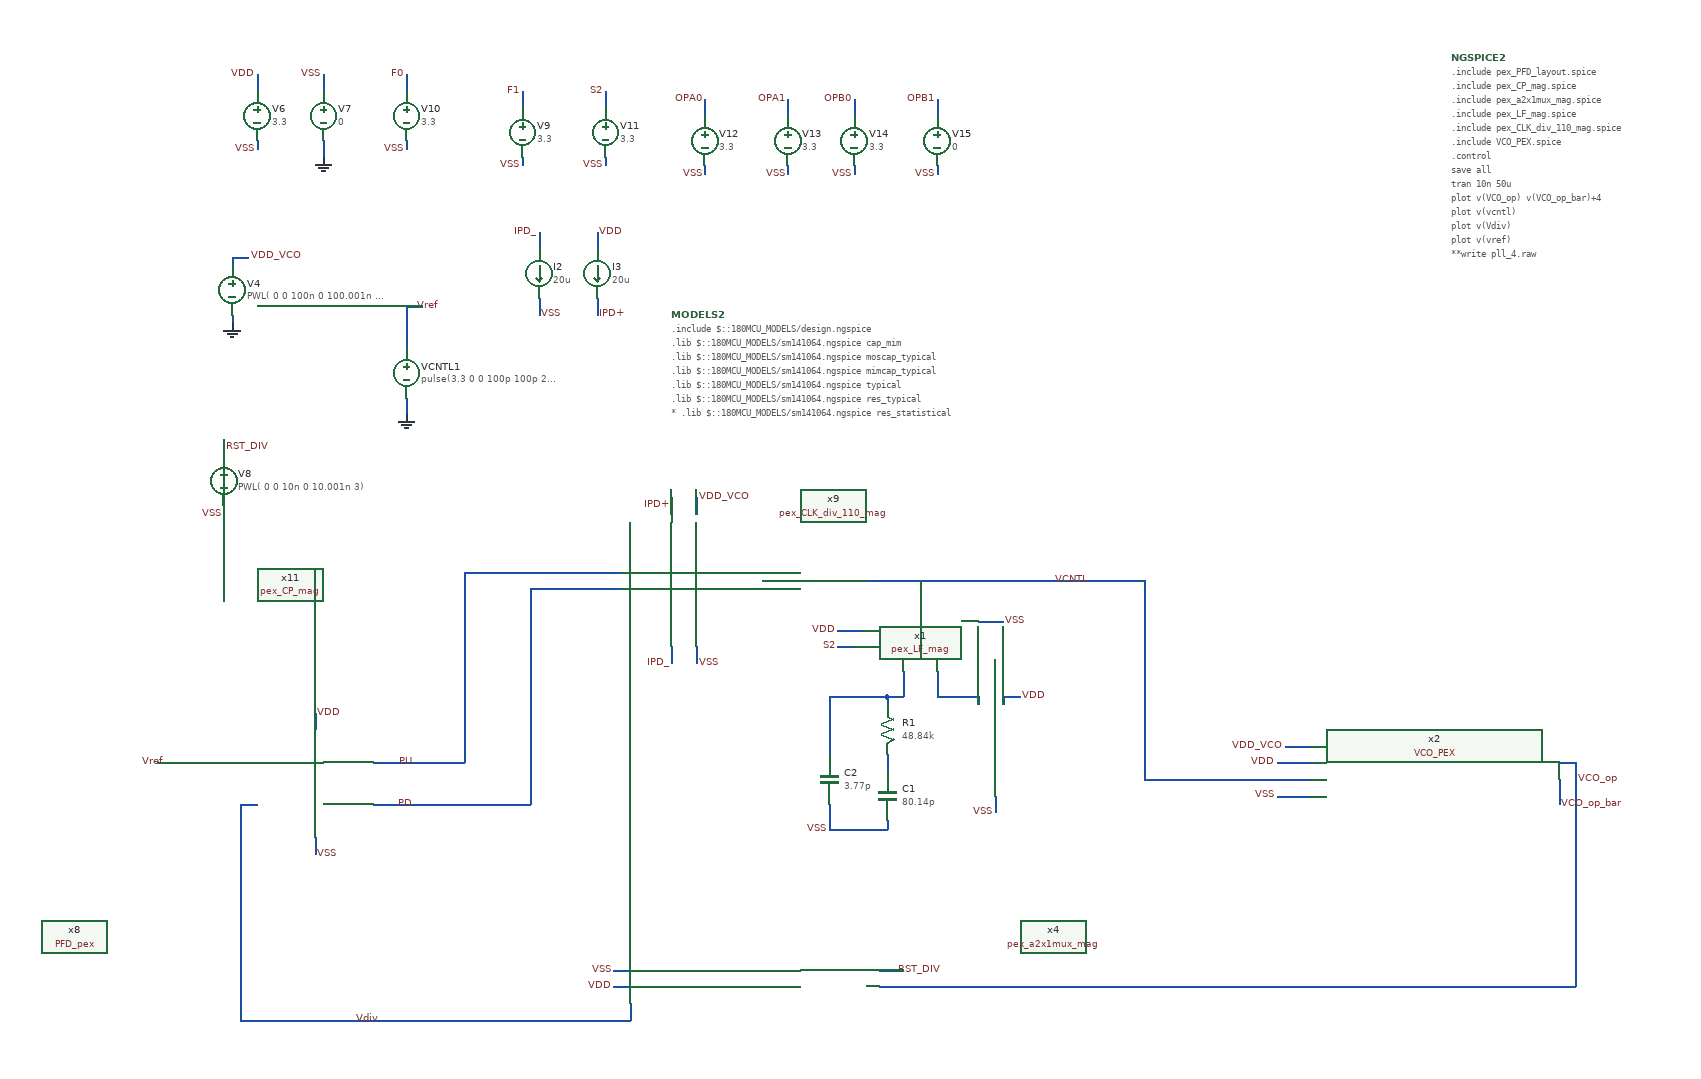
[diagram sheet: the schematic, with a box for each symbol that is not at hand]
v {xschem version=3.1.0 file_version=1.2
}
G {}
K {}
V {}
S {}
E {}
N 270 -490 270 -470 {
lab=VDD}
N 270 -340 270 -320 {
lab=VSS}
N 180 -430 200 -430 {
lab=Vref}
N 180 -380 200 -380 {
lab=Vdiv}
N 340 -380 360 -380 {
lab=PD}
N 100 -430 160 -430 {
lab=Vref}
N 160 -430 180 -430 {
lab=Vref}
N 360 -430 450 -430 {
lab=PU}
N 360 -380 450 -380 {
lab=PD}
N 180 -380 180 -250 {
lab=Vdiv}
N 180 -150 180 -120 {
lab=Vdiv}
N 190 -120 480 -120 {
lab=Vdiv}
N 180 -250 180 -150 {
lab=Vdiv}
N 180 -120 190 -120 {
lab=Vdiv}
N 340 -430 360 -430 {
lab=PU}
N 380 -870 380 -850 {
lab=GND}
N 170 -970 170 -960 {
lab=GND}
N 380 -980 400 -980 {
lab=Vref}
N 200 -1180 200 -1170 {
lab=VSS}
N 200 -1260 200 -1240 {
lab=VDD}
N 280 -1260 280 -1240 {
lab=VSS}
N 280 -1180 280 -1160 {
lab=GND}
N 480 -120 650 -120 {
lab=Vdiv}
N 980 -160 1630 -160 {
lab=VCO_op}
N 160 -740 160 -730 {
lab=VSS}
N 160 -820 160 -800 {
lab=RST_DIV}
N 1790 -410 1790 -390 {
lab=VCO_op}
N 380 -980 380 -930 {
lab=Vref}
N 950 -160 970 -160 {
lab=VCO_op}
N 970 -160 980 -160 {
lab=VCO_op}
N 170 -1040 170 -1030 {
lab=VDD_VCO}
N 170 -1040 190 -1040 {
lab=VDD_VCO}
N 520 -1160 520 -1150 {
lab=VSS}
N 520 -1240 520 -1220 {
lab=F1}
N 380 -1180 380 -1170 {
lab=VSS}
N 380 -1260 380 -1240 {
lab=F0}
N 620 -1160 620 -1150 {
lab=VSS}
N 620 -1240 620 -1220 {
lab=S2}
N 740 -1150 740 -1140 {
lab=VSS}
N 740 -1230 740 -1210 {
lab=OPA0}
N 840 -1150 840 -1140 {
lab=VSS}
N 840 -1230 840 -1210 {
lab=OPA1}
N 920 -1150 920 -1140 {
lab=VSS}
N 920 -1230 920 -1210 {
lab=OPB0}
N 1020 -1150 1020 -1140 {
lab=VSS}
N 1020 -1230 1020 -1210 {
lab=OPB1}
N 730 -750 730 -730 {
lab=VDD_VCO}
N 730 -570 730 -550 {
lab=VSS}
N 620 -660 640 -660 {
lab=PU}
N 620 -640 640 -640 {
lab=PD}
N 700 -750 700 -730 {
lab=IPD+}
N 700 -570 700 -550 {
lab=IPD_}
N 540 -990 540 -970 {
lab=VSS}
N 610 -990 610 -970 {
lab=IPD+}
N 540 -1070 540 -1050 {
lab=IPD_}
N 610 -1070 610 -1050 {
lab=VDD}
N 80 -430 110 -430 {
lab=Vref}
N 1270 -410 1310 -410 {
lab=VCNTL}
N 1790 -430 1790 -410 {
lab=VCO_op}
N 1770 -430 1790 -430 {
lab=VCO_op}
N 1770 -410 1770 -380 {
lab=VCO_op_bar}
N 650 -140 650 -120 {
lab=Vdiv}
N 640 -160 650 -160 {
lab=VDD}
N 630 -160 640 -160 {
lab=VDD}
N 630 -180 650 -180 {
lab=VSS}
N 950 -180 980 -180 {
lab=RST_DIV}
N 1440 -450 1470 -450 {
lab=VDD_VCO}
N 1310 -410 1470 -410 {
lab=VCNTL}
N 1090 -390 1090 -370 {
lab=VSS}
N 1100 -510 1100 -500 {
lab=VDD}
N 1100 -510 1120 -510 {
lab=VDD}
N 900 -570 920 -570 {
lab=S2}
N 900 -590 920 -590 {
lab=VDD}
N 1070 -600 1100 -600 {
lab=VSS}
N 890 -380 890 -350 {
lab=VSS}
N 890 -350 960 -350 {
lab=VSS}
N 890 -510 890 -440 {
lab=#net1}
N 890 -510 960 -510 {
lab=#net1}
N 960 -510 960 -500 {
lab=#net1}
N 920 -590 930 -590 {
lab=VDD}
N 880 -650 1060 -650 {
lab=VCNTL}
N 960 -440 960 -420 {
lab=#net2}
N 960 -360 960 -350 {
lab=VSS}
N 960 -510 980 -510 {
lab=#net1}
N 980 -540 980 -510 {
lab=#net1}
N 1070 -510 1070 -500 {
lab=#net3}
N 1020 -510 1070 -510 {
lab=#net3}
N 1020 -540 1020 -510 {
lab=#net3}
N 1000 -650 1000 -640 {
lab=VCNTL}
N 1270 -640 1270 -410 {
lab=VCNTL}
N 1270 -650 1270 -640 {
lab=VCNTL}
N 1060 -650 1270 -650 {
lab=VCNTL}
N 810 -650 880 -650 {
lab=VCNTL}
N 450 -660 620 -660 {
lab=PU}
N 450 -660 450 -430 {
lab=PU}
N 450 -380 530 -380 {
lab=PD}
N 530 -640 530 -380 {
lab=PD}
N 530 -640 620 -640 {
lab=PD}
N 1430 -390 1470 -390 {
lab=VSS}
N 1430 -430 1470 -430 {
lab=VDD}
N 1790 -390 1790 -160 {
lab=VCO_op}
N 1630 -160 1790 -160 {
lab=VCO_op}
C {devices/lab_pin.sym} 270 -490 2 0 {name=p22 sig_type=std_logic lab=VDD}
C {devices/lab_wire.sym} 270 -320 2 0 {name=p23 sig_type=std_logic lab=VSS}
C {devices/lab_pin.sym} 350 -120 3 0 {name=p25 sig_type=std_logic lab=Vdiv
}
C {devices/lab_pin.sym} 1790 -410 2 0 {name=p26 sig_type=std_logic lab=VCO_op
}
C {devices/vsource.sym} 380 -900 0 0 {name=VCNTL1 value="pulse(3.3 0 0 100p 100p 250n 500n)"}
C {devices/gnd.sym} 380 -850 0 0 {name=l4 lab=GND}
C {devices/gnd.sym} 170 -960 0 0 {name=l5 lab=GND}
C {devices/vsource.sym} 170 -1000 0 0 {name=V4 value=" PWL( 0 0 100n 0 100.001n 3.3)"}
C {devices/code_shown.sym} 1640 -1280 0 1 {name=NGSPICE2 only_toplevel=true
value="
.include "pex_PFD_layout.spice"
.include "pex_CP_mag.spice"
.include "pex_a2x1mux_mag.spice"
.include "pex_LF_mag.spice"
.include "pex_CLK_div_110_mag.spice"
.include "VCO_PEX.spice"
.control
save all
tran 10n 50u 
plot v(VCO_op) v(VCO_op_bar)+4
plot v(vcntl)
plot v(Vdiv)
plot v(vref)
**write pll_4.raw
.endc
"}
C {devices/vsource.sym} 200 -1210 0 0 {name=V6 value=3.3}
C {devices/vsource.sym} 280 -1210 0 0 {name=V7 value=0}
C {devices/lab_wire.sym} 280 -1260 0 0 {name=p27 sig_type=std_logic lab=VSS}
C {devices/lab_wire.sym} 200 -1170 0 0 {name=p29 sig_type=std_logic lab=VSS
}
C {devices/lab_wire.sym} 200 -1260 0 0 {name=p30 sig_type=std_logic lab=VDD}
C {devices/gnd.sym} 280 -1160 0 0 {name=l6 lab=GND}
C {devices/lab_pin.sym} 1770 -380 2 0 {name=p31 sig_type=std_logic lab=VCO_op_bar
}
C {devices/lab_pin.sym} 190 -1040 2 0 {name=p32 sig_type=std_logic lab=VDD_VCO}
C {devices/lab_pin.sym} 390 -980 2 0 {name=p33 sig_type=std_logic lab=Vref
}
C {devices/lab_wire.sym} 160 -730 0 0 {name=p34 sig_type=std_logic lab=VSS
}
C {devices/vsource.sym} 160 -770 0 0 {name=V8 value=" PWL( 0 0 10n 0 10.001n 3)"}
C {devices/lab_pin.sym} 390 -430 1 0 {name=p37 sig_type=std_logic lab=PU}
C {devices/lab_pin.sym} 390 -380 1 0 {name=p40 sig_type=std_logic lab=PD}
C {devices/vsource.sym} 520 -1190 0 0 {name=V9 value=3.3}
C {devices/lab_wire.sym} 520 -1150 0 0 {name=p41 sig_type=std_logic lab=VSS
}
C {devices/lab_wire.sym} 520 -1240 0 0 {name=p42 sig_type=std_logic lab=F1}
C {devices/vsource.sym} 380 -1210 0 0 {name=V10 value=3.3}
C {devices/lab_wire.sym} 380 -1170 0 0 {name=p43 sig_type=std_logic lab=VSS
}
C {devices/lab_wire.sym} 380 -1260 0 0 {name=p44 sig_type=std_logic lab=F0}
C {devices/vsource.sym} 620 -1190 0 0 {name=V11 value=3.3}
C {devices/lab_wire.sym} 620 -1150 0 0 {name=p45 sig_type=std_logic lab=VSS
}
C {devices/lab_wire.sym} 620 -1240 0 0 {name=p46 sig_type=std_logic lab=S2}
C {devices/vsource.sym} 740 -1180 0 0 {name=V12 value=3.3}
C {devices/lab_wire.sym} 740 -1140 0 0 {name=p59 sig_type=std_logic lab=VSS
}
C {devices/lab_wire.sym} 740 -1230 0 0 {name=p60 sig_type=std_logic lab=OPA0}
C {devices/vsource.sym} 840 -1180 0 0 {name=V13 value=3.3}
C {devices/lab_wire.sym} 840 -1140 0 0 {name=p61 sig_type=std_logic lab=VSS
}
C {devices/lab_wire.sym} 840 -1230 0 0 {name=p62 sig_type=std_logic lab=OPA1}
C {devices/vsource.sym} 920 -1180 0 0 {name=V14 value=3.3}
C {devices/lab_wire.sym} 920 -1140 0 0 {name=p63 sig_type=std_logic lab=VSS
}
C {devices/lab_wire.sym} 920 -1230 0 0 {name=p64 sig_type=std_logic lab=OPB0
}
C {devices/vsource.sym} 1020 -1180 0 0 {name=V15 value=0}
C {devices/lab_wire.sym} 1020 -1140 0 0 {name=p65 sig_type=std_logic lab=VSS
}
C {devices/lab_wire.sym} 1020 -1230 0 0 {name=p66 sig_type=std_logic lab=OPB1}
C {devices/lab_pin.sym} 160 -810 2 0 {name=p67 sig_type=std_logic lab=RST_DIV}
C {devices/lab_wire.sym} 730 -550 2 0 {name=p68 sig_type=std_logic lab=VSS}
C {devices/lab_wire.sym} 700 -740 0 0 {name=p70 sig_type=std_logic lab=IPD+}
C {devices/lab_wire.sym} 700 -550 0 0 {name=p71 sig_type=std_logic lab=IPD_}
C {devices/isource.sym} 540 -1020 0 0 {name=I2 value=20u}
C {devices/isource.sym} 610 -1020 0 0 {name=I3 value=20u}
C {devices/lab_wire.sym} 540 -1070 0 0 {name=p72 sig_type=std_logic lab=IPD_}
C {devices/lab_wire.sym} 610 -970 2 0 {name=p73 sig_type=std_logic lab=IPD+}
C {devices/lab_wire.sym} 540 -970 2 0 {name=p74 sig_type=std_logic lab=VSS}
C {devices/lab_wire.sym} 610 -1070 2 0 {name=p75 sig_type=std_logic lab=VDD}
C {devices/lab_pin.sym} 90 -430 0 0 {name=p76 sig_type=std_logic lab=Vref
}
C {devices/code_shown.sym} 700 -970 0 0 {name=MODELS2 only_toplevel=true
format="tcleval( @value )"
value="
.include $::180MCU_MODELS/design.ngspice
.lib $::180MCU_MODELS/sm141064.ngspice cap_mim
.lib $::180MCU_MODELS/sm141064.ngspice moscap_typical
.lib $::180MCU_MODELS/sm141064.ngspice mimcap_typical
.lib $::180MCU_MODELS/sm141064.ngspice typical
.lib $::180MCU_MODELS/sm141064.ngspice res_typical
* .lib $::180MCU_MODELS/sm141064.ngspice res_statistical
"}
C {PFD_pex.sym} -20 -220 0 0 {name=x8}
C {devices/lab_wire.sym} 630 -180 0 0 {name=p78 sig_type=std_logic lab=VSS}
C {devices/lab_pin.sym} 630 -160 0 0 {name=p79 sig_type=std_logic lab=VDD}
C {devices/lab_pin.sym} 970 -180 2 0 {name=p80 sig_type=std_logic lab=RST_DIV}
C {pex_CLK_div_110_mag.sym} 800 -160 0 1 {name=x9}
C {pex_CP_mag.sym} 150 -450 0 0 {name=x11}
C {devices/lab_pin.sym} 730 -750 2 0 {name=p81 sig_type=std_logic lab=VDD_VCO}
C {devices/lab_pin.sym} 1440 -450 0 0 {name=p89 sig_type=std_logic lab=VDD_VCO}
C {devices/lab_wire.sym} 1090 -370 2 1 {name=p5 sig_type=std_logic lab=VSS}
C {devices/lab_wire.sym} 1160 -650 2 0 {name=p20 sig_type=std_logic lab=VCNTL}
C {devices/lab_wire.sym} 1120 -510 0 1 {name=p21 sig_type=std_logic lab=VDD}
C {devices/lab_wire.sym} 1100 -600 2 0 {name=p6 sig_type=std_logic lab=VSS}
C {devices/lab_wire.sym} 900 -590 2 1 {name=p1 sig_type=std_logic lab=VDD}
C {devices/lab_wire.sym} 900 -570 1 1 {name=p2 sig_type=std_logic lab=S2}
C {devices/capa.sym} 960 -390 0 0 {name=C1
m=1
value=80.14p
footprint=1206
device="ceramic capacitor"}
C {devices/capa.sym} 890 -410 0 0 {name=C2
m=1
value=3.77p
footprint=1206
device="ceramic capacitor"}
C {devices/res.sym} 960 -470 0 0 {name=R1
value=48.84k
footprint=1206
device=resistor
m=1}
C {devices/lab_wire.sym} 890 -350 2 1 {name=p3 sig_type=std_logic lab=VSS}
C {pex_a2x1mux_mag.sym} 1160 -220 3 0 {name=x4}
C {pex_LF_mag.sym} 1230 -340 0 1 {name=x1}
C {VCO_PEX.sym} 1620 -420 0 0 {name=x2}
C {devices/lab_wire.sym} 1430 -390 2 1 {name=p4 sig_type=std_logic lab=VSS}
C {devices/lab_pin.sym} 1430 -430 0 0 {name=p7 sig_type=std_logic lab=VDD}
